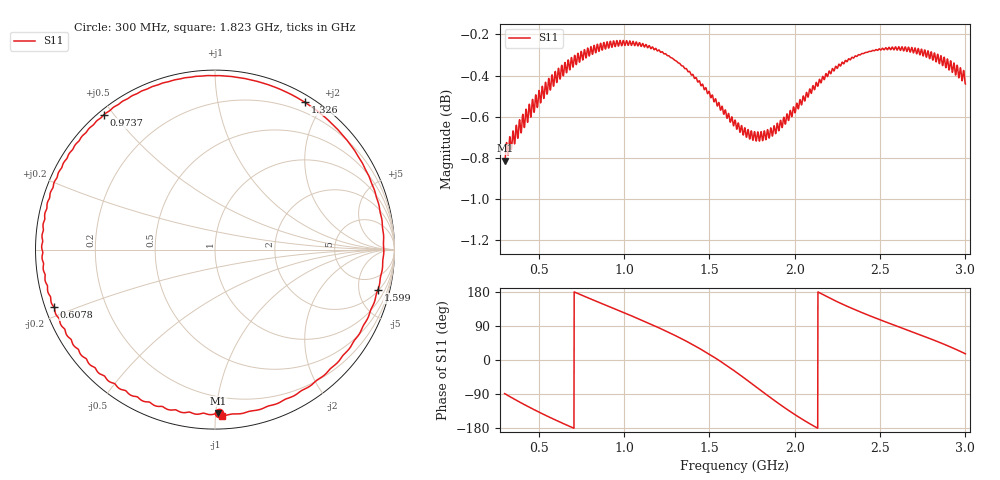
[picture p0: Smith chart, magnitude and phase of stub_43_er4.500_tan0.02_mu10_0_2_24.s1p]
! Chirptenna · simulación 3D de un stub abierto
# HZ S RI R 50
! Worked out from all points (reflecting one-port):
!   2001 points, 300 MHz to 3 GHz, reference 50 ohm
!   lowest |S11| = -0.8 dB at 301.4 MHz (marker M1), VSWR 21.37, Z = 4.76 - j50.7 ohm
!   phase of S11 starts at -89 deg and turns -615 deg over the sweep
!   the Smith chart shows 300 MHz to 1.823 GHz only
!   S11 on the Smith chart (normalised r, x): 300 MHz: 0.10, -1.02; 607.8 MHz: 0.03, -0.17; 973.6 MHz: 0.02, +0.47; 1.326 GHz: 0.08, +1.78; 1.599 GHz: 2.14, -7.59; 1.823 GHz: 0.08, -1.04
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3e8  0.0206 -0.9107
3.0135e8  0.0165 -0.9104
4.3365e8  -0.4951 -0.7879
5.1465e8  -0.7257 -0.6027
6.078e8  -0.8959 -0.3217
6.375e8  -0.9332 -0.2225
7.9545e8  -0.9221 0.2861
9.7365e8  -0.6206 0.7498
9.75e8  -0.6172 0.7531
1.1559e9  -0.0788 0.9664
1.3125e9  0.4565 0.847
1.326e9  0.5005 0.821
1.4745e9  0.879 0.355
1.542e9  0.9391 0.0495
1.5987e9  0.9069 -0.2251
1.65e9  0.8072 -0.4649
1.7391e9  0.472 -0.7927
1.8228e9  0.0385 -0.925
1.9038e9  -0.3824 -0.8445
1.9875e9  -0.7164 -0.6016
2.0604e9  -0.8891 -0.3106
2.13735e9  -0.9498 0.00971
2.2278e9  -0.8901 0.3533
2.325e9  -0.7184 0.6419
2.48835e9  -0.3018 0.9205
2.6625e9  0.1902 0.9504
2.8272e9  0.6164 0.7394
3e9  0.9123 0.2669
